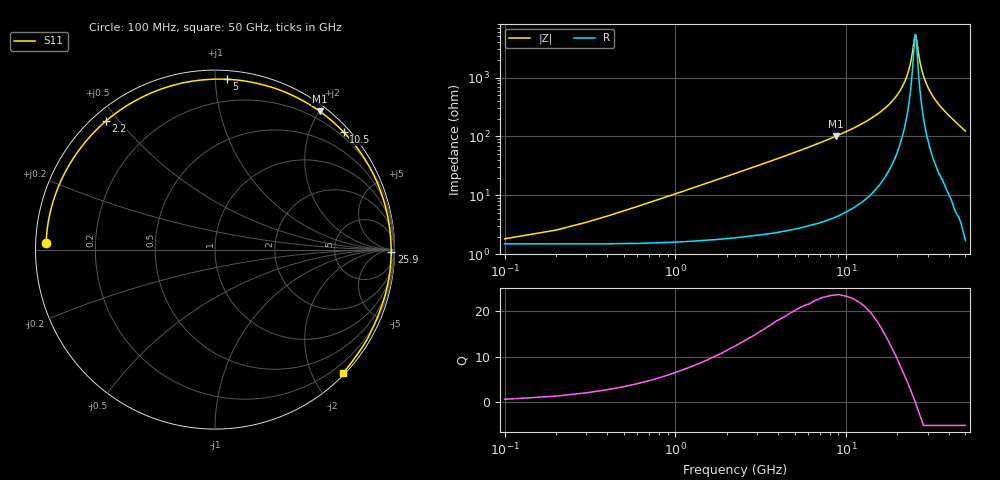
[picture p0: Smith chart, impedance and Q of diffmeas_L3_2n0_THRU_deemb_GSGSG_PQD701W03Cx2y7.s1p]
! Created Wed Mar 15 13:51:37 2023
# hz S ma R 50
! 1 Port Network Data from SP1.SP block
! freq  magS11  angS11
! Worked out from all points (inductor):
!   500 points, 100 MHz to 50 GHz, reference 50 ohm
!   read as one part to ground: L = 1.67 nH near 500 MHz
!   highest Q = 23.4 at 8.7 GHz (marker M1), where L = 1.84 nH
!   self-resonance near 25.48 GHz
!   S11 on the Smith chart (normalised r, x): 100 MHz: 0.03, +0.02; 2.2 GHz: 0.04, +0.46; 5 GHz: 0.05, +1.07; 10.5 GHz: 0.11, +2.57; 25.9 GHz: 70, -52; 50 GHz: 0.03, -2.47
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1e8  0.9413 177.6
3e8  0.9418 172.8
5e8  0.9413 168.0
1e9  0.9401 156.2
1.6e9  0.9386 142.8
2.2e9  0.9392 130.4
2.8e9  0.9407 119.0
3.5e9  0.9438 107.0
4.2e9  0.9473 96.5
5e9  0.9514 86.0
5.7e9  0.9548 77.9
6.4e9  0.9579 70.9
7.5e9  0.9625 61.4
8.7e9  0.9666 52.8
9.5e9  0.9687 47.8
1.05e10  0.971 42.4
1.15e10  0.9728 37.6
1.26e10  0.9747 32.9
1.39e10  0.9763 28.1
1.54e10  0.9776 23.1
1.89e10  0.9793 13.6
2.18e10  0.9801 7.2
2.51e10  0.9814 0.7
2.59e10  0.9818 -0.8
3.13e10  0.9817 -10.2
3.76e10  0.9801 -20.7
4.38e10  0.9842 -31.6
5e10  0.9904 -44.0
